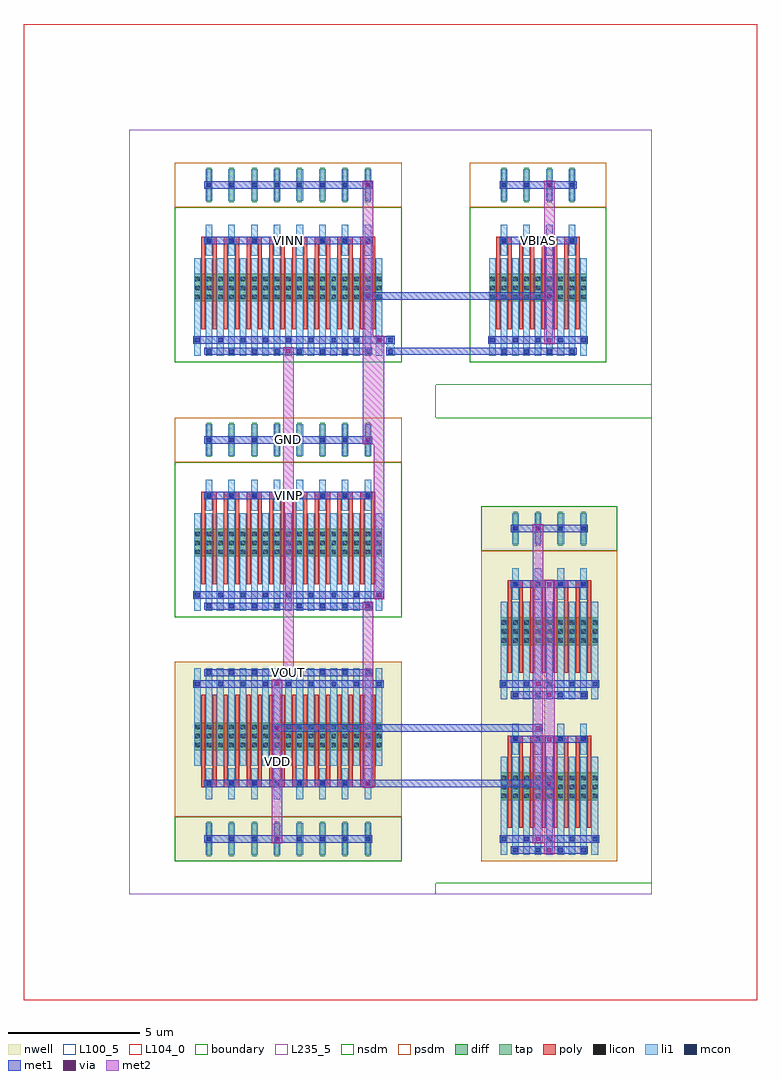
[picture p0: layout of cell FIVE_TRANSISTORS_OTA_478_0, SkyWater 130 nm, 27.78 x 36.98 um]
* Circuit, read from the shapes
.subckt FIVE_TRANSISTORS_OTA_478_0 GND VBIAS VDD VINN VINP VOUT
XM1 n1 VINP n2 GND sky130_fd_pr__nfet_01v8 w=1.05 l=0.15 m=16
XM2 VOUT VINN n2 GND sky130_fd_pr__nfet_01v8 w=1.05 l=0.15 m=16
XM3 n2 VBIAS GND GND sky130_fd_pr__nfet_01v8 w=1.05 l=0.15 m=8
XM4 VOUT n1 VDD VDD sky130_fd_pr__pfet_01v8 w=1.05 l=0.15 m=16
XM5 n1 n1 VDD VDD sky130_fd_pr__pfet_01v8 w=1.05 l=0.15 m=16
.ends

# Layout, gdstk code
from math import pi, radians
import gdstk
lib = gdstk.Library(unit=1e-6, precision=1e-09)
def R(c, l, rs):  # rectangles x0, y0, x1, y1
    for r in rs: c.add(gdstk.rectangle(r[:2], r[2:], *l))
def A(c, l, x, y, w, h, nx, ny, dx, dy):  # array of equal rectangles
    R(c, l, [(x+i*dx, y+j*dy, x+i*dx+w, y+j*dy+h) for i in range(nx) for j in range(ny)])
def P(c, l, *ps):  # polygons
    for p in ps: c.add(gdstk.Polygon(p, *l))
nwell = (64, 20)
diff = (65, 20)
tap = (65, 44)
poly = (66, 20)
licon = (66, 44)
li1 = (67, 20)
mcon = (67, 44)
met1 = (68, 20)
via = (68, 44)
met2 = (69, 20)
nsdm = (93, 44)
psdm = (94, 20)
L100_5 = (100, 5)
L104_0 = (104, 0)
boundary = (235, 4)
L235_5 = (235, 5)

dcl_pmos_s_58408510_x4_y = lib.new_cell('DCL_PMOS_S_58408510_X4_Y2_1746735249')
R(dcl_pmos_s_58408510_x4_y, nwell, [(1.29,0.84,6.45,14.28)])
R(dcl_pmos_s_58408510_x4_y, diff, [(2.025,3.15,5.715,4.2), (2.025,9.03,5.715,10.08)])
A(dcl_pmos_s_58408510_x4_y, tap, 2.495, 12.795, 0.17, 1.29, 4, 1, 0.86, 0)
A(dcl_pmos_s_58408510_x4_y, poly, 2.29, 2.1, 0.15, 3.36, 8, 2, 0.43, 5.88)
A(dcl_pmos_s_58408510_x4_y, poly, 2.29, 5.325, 0.58, 0.27, 4, 2, 0.86, 5.88)
A(dcl_pmos_s_58408510_x4_y, licon, 2.065, 3.23, 0.17, 0.17, 3, 3, 0.43, 0.34)
A(dcl_pmos_s_58408510_x4_y, licon, 2.925, 3.23, 0.17, 0.17, 3, 3, 0.43, 0.34)
A(dcl_pmos_s_58408510_x4_y, licon, 3.785, 3.23, 0.17, 0.17, 3, 3, 0.43, 0.34)
A(dcl_pmos_s_58408510_x4_y, licon, 4.645, 3.23, 0.17, 0.17, 3, 3, 0.43, 0.34)
A(dcl_pmos_s_58408510_x4_y, licon, 2.495, 5.375, 0.17, 0.17, 4, 2, 0.86, 5.88)
A(dcl_pmos_s_58408510_x4_y, licon, 2.065, 9.11, 0.17, 0.17, 3, 3, 0.43, 0.34)
A(dcl_pmos_s_58408510_x4_y, licon, 2.925, 9.11, 0.17, 0.17, 3, 3, 0.43, 0.34)
A(dcl_pmos_s_58408510_x4_y, licon, 3.785, 9.11, 0.17, 0.17, 3, 3, 0.43, 0.34)
A(dcl_pmos_s_58408510_x4_y, licon, 4.645, 9.11, 0.17, 0.17, 3, 3, 0.43, 0.34)
R(dcl_pmos_s_58408510_x4_y, licon, [(2.495,13.355,2.665,13.525), (2.495,13.355,2.665,13.525), (3.355,13.355,3.525,13.525), (3.355,13.355,3.525,13.525), (4.215,13.355,4.385,13.525), (4.215,13.355,4.385,13.525), (5.075,13.355,5.245,13.525), (5.075,13.355,5.245,13.525)])
A(dcl_pmos_s_58408510_x4_y, li1, 2.025, 1.09, 0.25, 3.7, 9, 2, 0.43, 5.88)
A(dcl_pmos_s_58408510_x4_y, li1, 2.455, 4.87, 0.25, 1.18, 4, 2, 0.86, 5.88)
A(dcl_pmos_s_58408510_x4_y, li1, 2.455, 12.85, 0.25, 1.18, 4, 1, 0.86, 0)
A(dcl_pmos_s_58408510_x4_y, mcon, 2.495, 1.175, 0.17, 0.17, 4, 2, 0.86, 4.2)
A(dcl_pmos_s_58408510_x4_y, mcon, 2.065, 1.595, 0.17, 0.17, 5, 2, 0.86, 5.88)
A(dcl_pmos_s_58408510_x4_y, mcon, 2.495, 7.055, 0.17, 0.17, 4, 2, 0.86, 4.2)
A(dcl_pmos_s_58408510_x4_y, mcon, 2.495, 13.355, 0.17, 0.17, 4, 1, 0.86, 0)
R(dcl_pmos_s_58408510_x4_y, met1, [(2.41,1.12,5.33,1.4), (1.98,1.54,5.76,1.82), (2.41,5.32,5.33,5.6), (2.41,7,5.33,7.28), (1.98,7.42,5.76,7.7), (2.41,11.2,5.33,11.48), (2.41,13.3,5.33,13.58)])
A(dcl_pmos_s_58408510_x4_y, via, 4.225, 1.605, 0.15, 0.15, 1, 3, 0, 5.88)
R(dcl_pmos_s_58408510_x4_y, via, [(3.795,1.185,3.945,1.335), (3.795,5.385,3.945,5.535), (3.795,7.065,3.945,7.215), (3.795,11.265,3.945,11.415)])
R(dcl_pmos_s_58408510_x4_y, met2, [(3.67,1.1,4.07,11.5), (4.1,1.52,4.5,13.6)])
R(dcl_pmos_s_58408510_x4_y, nsdm, [(1.29,12.6,6.45,14.28)])
R(dcl_pmos_s_58408510_x4_y, psdm, [(1.29,0.84,6.45,12.6)])
R(dcl_pmos_s_58408510_x4_y, L100_5, [(0,0,8.17,17.64)])
R(dcl_pmos_s_58408510_x4_y, boundary, [(0,0,8.17,17.64)])

nmos_s_69925134_x4_y1_17 = lib.new_cell('NMOS_S_69925134_X4_Y1_1746735252')
R(nmos_s_69925134_x4_y1_17, diff, [(2.025,3.15,5.715,4.2)])
A(nmos_s_69925134_x4_y1_17, tap, 2.495, 6.915, 0.17, 1.29, 4, 1, 0.86, 0)
A(nmos_s_69925134_x4_y1_17, poly, 2.29, 2.1, 0.15, 3.36, 8, 1, 0.43, 0)
A(nmos_s_69925134_x4_y1_17, poly, 2.29, 5.325, 0.58, 0.27, 4, 1, 0.86, 0)
A(nmos_s_69925134_x4_y1_17, licon, 2.065, 3.23, 0.17, 0.17, 3, 3, 0.43, 0.34)
A(nmos_s_69925134_x4_y1_17, licon, 2.925, 3.23, 0.17, 0.17, 3, 3, 0.43, 0.34)
A(nmos_s_69925134_x4_y1_17, licon, 3.785, 3.23, 0.17, 0.17, 3, 3, 0.43, 0.34)
A(nmos_s_69925134_x4_y1_17, licon, 4.645, 3.23, 0.17, 0.17, 3, 3, 0.43, 0.34)
A(nmos_s_69925134_x4_y1_17, licon, 2.495, 5.375, 0.17, 0.17, 4, 2, 0.86, 2.1)
A(nmos_s_69925134_x4_y1_17, li1, 2.025, 1.09, 0.25, 3.7, 9, 1, 0.43, 0)
A(nmos_s_69925134_x4_y1_17, li1, 2.455, 4.87, 0.25, 1.18, 4, 2, 0.86, 2.1)
A(nmos_s_69925134_x4_y1_17, mcon, 2.495, 1.175, 0.17, 0.17, 4, 2, 0.86, 4.2)
A(nmos_s_69925134_x4_y1_17, mcon, 2.065, 1.595, 0.17, 0.17, 5, 1, 0.86, 0)
A(nmos_s_69925134_x4_y1_17, mcon, 2.495, 7.475, 0.17, 0.17, 4, 1, 0.86, 0)
R(nmos_s_69925134_x4_y1_17, met1, [(2.41,1.12,5.33,1.4), (1.98,1.54,5.76,1.82), (2.41,5.32,5.33,5.6), (2.41,7.42,5.33,7.7)])
R(nmos_s_69925134_x4_y1_17, via, [(4.225,1.605,4.375,1.755), (4.225,7.485,4.375,7.635)])
R(nmos_s_69925134_x4_y1_17, met2, [(4.1,1.52,4.5,7.72)])
R(nmos_s_69925134_x4_y1_17, nsdm, [(1.29,0.84,6.45,6.72)])
R(nmos_s_69925134_x4_y1_17, psdm, [(1.29,6.72,6.45,8.4)])
R(nmos_s_69925134_x4_y1_17, L100_5, [(0,0,8.17,9.66)])
R(nmos_s_69925134_x4_y1_17, boundary, [(0,0,8.17,9.66)])

pmos_s_35671219_x8_y1_17 = lib.new_cell('PMOS_S_35671219_X8_Y1_1746735253')
R(pmos_s_35671219_x8_y1_17, nwell, [(1.29,0.84,9.89,8.4)])
R(pmos_s_35671219_x8_y1_17, diff, [(2.025,3.15,9.155,4.2)])
A(pmos_s_35671219_x8_y1_17, tap, 2.495, 6.915, 0.17, 1.29, 8, 1, 0.86, 0)
A(pmos_s_35671219_x8_y1_17, poly, 2.29, 2.1, 0.15, 3.36, 16, 1, 0.43, 0)
A(pmos_s_35671219_x8_y1_17, poly, 2.29, 5.325, 0.58, 0.27, 8, 1, 0.86, 0)
A(pmos_s_35671219_x8_y1_17, licon, 2.065, 3.23, 0.17, 0.17, 3, 3, 0.43, 0.34)
A(pmos_s_35671219_x8_y1_17, licon, 2.925, 3.23, 0.17, 0.17, 3, 3, 0.43, 0.34)
A(pmos_s_35671219_x8_y1_17, licon, 3.785, 3.23, 0.17, 0.17, 3, 3, 0.43, 0.34)
A(pmos_s_35671219_x8_y1_17, licon, 4.645, 3.23, 0.17, 0.17, 3, 3, 0.43, 0.34)
A(pmos_s_35671219_x8_y1_17, licon, 5.505, 3.23, 0.17, 0.17, 3, 3, 0.43, 0.34)
A(pmos_s_35671219_x8_y1_17, licon, 6.365, 3.23, 0.17, 0.17, 3, 3, 0.43, 0.34)
A(pmos_s_35671219_x8_y1_17, licon, 7.225, 3.23, 0.17, 0.17, 3, 3, 0.43, 0.34)
A(pmos_s_35671219_x8_y1_17, licon, 8.085, 3.23, 0.17, 0.17, 3, 3, 0.43, 0.34)
A(pmos_s_35671219_x8_y1_17, licon, 2.495, 5.375, 0.17, 0.17, 8, 2, 0.86, 2.1)
A(pmos_s_35671219_x8_y1_17, li1, 2.025, 1.09, 0.25, 3.7, 17, 1, 0.43, 0)
A(pmos_s_35671219_x8_y1_17, li1, 2.455, 4.87, 0.25, 1.18, 8, 2, 0.86, 2.1)
A(pmos_s_35671219_x8_y1_17, mcon, 2.495, 1.175, 0.17, 0.17, 8, 2, 0.86, 4.2)
A(pmos_s_35671219_x8_y1_17, mcon, 2.065, 1.595, 0.17, 0.17, 9, 1, 0.86, 0)
A(pmos_s_35671219_x8_y1_17, mcon, 2.495, 7.475, 0.17, 0.17, 8, 1, 0.86, 0)
R(pmos_s_35671219_x8_y1_17, met1, [(2.41,1.12,8.77,1.4), (1.98,1.54,9.2,1.82), (2.41,5.32,8.77,5.6), (2.41,7.42,8.77,7.7)])
R(pmos_s_35671219_x8_y1_17, via, [(5.945,1.605,6.095,1.755), (5.945,7.485,6.095,7.635)])
R(pmos_s_35671219_x8_y1_17, met2, [(5.82,1.52,6.22,7.72)])
R(pmos_s_35671219_x8_y1_17, nsdm, [(1.29,6.72,9.89,8.4)])
R(pmos_s_35671219_x8_y1_17, psdm, [(1.29,0.84,9.89,6.72)])
R(pmos_s_35671219_x8_y1_17, L100_5, [(0,0,11.61,9.66)])
R(pmos_s_35671219_x8_y1_17, boundary, [(0,0,11.61,9.66)])

nmos_4t_75119689_x8_y1_1 = lib.new_cell('NMOS_4T_75119689_X8_Y1_1746735251')
R(nmos_4t_75119689_x8_y1_1, diff, [(2.025,3.15,9.155,4.2)])
A(nmos_4t_75119689_x8_y1_1, tap, 2.495, 6.915, 0.17, 1.29, 8, 1, 0.86, 0)
A(nmos_4t_75119689_x8_y1_1, poly, 2.29, 2.1, 0.15, 3.36, 16, 1, 0.43, 0)
A(nmos_4t_75119689_x8_y1_1, poly, 2.29, 5.325, 0.58, 0.27, 8, 1, 0.86, 0)
A(nmos_4t_75119689_x8_y1_1, licon, 2.065, 3.23, 0.17, 0.17, 3, 3, 0.43, 0.34)
A(nmos_4t_75119689_x8_y1_1, licon, 2.925, 3.23, 0.17, 0.17, 3, 3, 0.43, 0.34)
A(nmos_4t_75119689_x8_y1_1, licon, 3.785, 3.23, 0.17, 0.17, 3, 3, 0.43, 0.34)
A(nmos_4t_75119689_x8_y1_1, licon, 4.645, 3.23, 0.17, 0.17, 3, 3, 0.43, 0.34)
A(nmos_4t_75119689_x8_y1_1, licon, 5.505, 3.23, 0.17, 0.17, 3, 3, 0.43, 0.34)
A(nmos_4t_75119689_x8_y1_1, licon, 6.365, 3.23, 0.17, 0.17, 3, 3, 0.43, 0.34)
A(nmos_4t_75119689_x8_y1_1, licon, 7.225, 3.23, 0.17, 0.17, 3, 3, 0.43, 0.34)
A(nmos_4t_75119689_x8_y1_1, licon, 8.085, 3.23, 0.17, 0.17, 3, 3, 0.43, 0.34)
A(nmos_4t_75119689_x8_y1_1, licon, 2.495, 5.375, 0.17, 0.17, 8, 2, 0.86, 2.1)
A(nmos_4t_75119689_x8_y1_1, li1, 2.025, 1.09, 0.25, 3.7, 17, 1, 0.43, 0)
A(nmos_4t_75119689_x8_y1_1, li1, 2.455, 4.87, 0.25, 1.18, 8, 2, 0.86, 2.1)
A(nmos_4t_75119689_x8_y1_1, mcon, 2.495, 1.175, 0.17, 0.17, 8, 2, 0.86, 4.2)
A(nmos_4t_75119689_x8_y1_1, mcon, 2.065, 1.595, 0.17, 0.17, 9, 1, 0.86, 0)
A(nmos_4t_75119689_x8_y1_1, mcon, 2.495, 7.475, 0.17, 0.17, 8, 1, 0.86, 0)
R(nmos_4t_75119689_x8_y1_1, met1, [(2.41,1.12,8.77,1.4), (1.98,1.54,9.2,1.82), (2.41,5.32,8.77,5.6), (2.41,7.42,8.77,7.7)])
R(nmos_4t_75119689_x8_y1_1, nsdm, [(1.29,0.84,9.89,6.72)])
R(nmos_4t_75119689_x8_y1_1, psdm, [(1.29,6.72,9.89,8.4)])
R(nmos_4t_75119689_x8_y1_1, L100_5, [(0,0,11.61,9.66)])
R(nmos_4t_75119689_x8_y1_1, boundary, [(0,0,11.61,9.66)])

nmos_4t_28601550_x8_y1_1 = lib.new_cell('NMOS_4T_28601550_X8_Y1_1746735250')
R(nmos_4t_28601550_x8_y1_1, diff, [(2.025,3.15,9.155,4.2)])
A(nmos_4t_28601550_x8_y1_1, tap, 2.495, 6.915, 0.17, 1.29, 8, 1, 0.86, 0)
A(nmos_4t_28601550_x8_y1_1, poly, 2.29, 2.1, 0.15, 3.36, 16, 1, 0.43, 0)
A(nmos_4t_28601550_x8_y1_1, poly, 2.29, 5.325, 0.58, 0.27, 8, 1, 0.86, 0)
A(nmos_4t_28601550_x8_y1_1, licon, 2.065, 3.23, 0.17, 0.17, 3, 3, 0.43, 0.34)
A(nmos_4t_28601550_x8_y1_1, licon, 2.925, 3.23, 0.17, 0.17, 3, 3, 0.43, 0.34)
A(nmos_4t_28601550_x8_y1_1, licon, 3.785, 3.23, 0.17, 0.17, 3, 3, 0.43, 0.34)
A(nmos_4t_28601550_x8_y1_1, licon, 4.645, 3.23, 0.17, 0.17, 3, 3, 0.43, 0.34)
A(nmos_4t_28601550_x8_y1_1, licon, 5.505, 3.23, 0.17, 0.17, 3, 3, 0.43, 0.34)
A(nmos_4t_28601550_x8_y1_1, licon, 6.365, 3.23, 0.17, 0.17, 3, 3, 0.43, 0.34)
A(nmos_4t_28601550_x8_y1_1, licon, 7.225, 3.23, 0.17, 0.17, 3, 3, 0.43, 0.34)
A(nmos_4t_28601550_x8_y1_1, licon, 8.085, 3.23, 0.17, 0.17, 3, 3, 0.43, 0.34)
A(nmos_4t_28601550_x8_y1_1, licon, 2.495, 5.375, 0.17, 0.17, 8, 2, 0.86, 2.1)
A(nmos_4t_28601550_x8_y1_1, li1, 2.025, 1.09, 0.25, 3.7, 17, 1, 0.43, 0)
A(nmos_4t_28601550_x8_y1_1, li1, 2.455, 4.87, 0.25, 1.18, 8, 2, 0.86, 2.1)
A(nmos_4t_28601550_x8_y1_1, mcon, 2.495, 1.175, 0.17, 0.17, 8, 2, 0.86, 4.2)
A(nmos_4t_28601550_x8_y1_1, mcon, 2.065, 1.595, 0.17, 0.17, 9, 1, 0.86, 0)
A(nmos_4t_28601550_x8_y1_1, mcon, 2.495, 7.475, 0.17, 0.17, 8, 1, 0.86, 0)
R(nmos_4t_28601550_x8_y1_1, met1, [(2.41,1.12,8.77,1.4), (1.98,1.54,9.2,1.82), (2.41,5.32,8.77,5.6), (2.41,7.42,8.77,7.7)])
R(nmos_4t_28601550_x8_y1_1, nsdm, [(1.29,0.84,9.89,6.72)])
R(nmos_4t_28601550_x8_y1_1, psdm, [(1.29,6.72,9.89,8.4)])
R(nmos_4t_28601550_x8_y1_1, L100_5, [(0,0,11.61,9.66)])
R(nmos_4t_28601550_x8_y1_1, boundary, [(0,0,11.61,9.66)])

five_transistors_ota_478 = lib.new_cell('FIVE_TRANSISTORS_OTA_478_0')
R(five_transistors_ota_478, li1, [(9.72,20.41,10.06,20.75), (9.72,20.41,10.06,20.75), (9.765,20.58,10.015,21), (9.72,20.83,10.06,21.17), (9.72,20.83,10.06,21.17)])
R(five_transistors_ota_478, mcon, [(9.805,20.495,9.975,20.665), (9.805,20.495,9.975,20.665), (9.805,20.915,9.975,21.085), (9.805,20.915,9.975,21.085)])
R(five_transistors_ota_478, met1, [(8.87,4.06,9.19,4.34), (8.87,4.06,9.19,4.34), (8.87,4.06,9.19,4.34), (8.87,4.06,9.19,4.34), (9.03,4.06,15.91,4.34), (15.75,4.06,16.07,4.34), (15.75,4.06,16.07,4.34), (5.43,6.16,5.75,6.44), (5.43,6.16,5.75,6.44), (5.59,6.16,15.48,6.44), (15.32,6.16,15.64,6.44), (15.32,6.16,15.64,6.44), (5.86,8.26,6.18,8.54), (5.86,8.26,6.18,8.54), (8.87,10.78,9.19,11.06), (8.87,10.78,9.19,11.06), (8.87,10.78,9.19,11.06), (8.87,10.78,9.19,11.06), (9.3,11.2,9.62,11.48), (9.3,11.2,9.62,11.48), (9.3,11.2,9.62,11.48), (9.3,11.2,9.62,11.48), (8.87,17.08,9.19,17.36), (8.87,17.08,9.19,17.36), (8.87,17.08,9.19,17.36), (8.87,17.08,9.19,17.36), (5.86,20.44,6.18,20.72), (5.86,20.44,6.18,20.72), (9.72,20.44,10.06,20.72), (9.72,20.44,10.06,20.72), (9.89,20.44,14.19,20.72), (9.3,20.86,9.62,21.14), (9.3,20.86,9.62,21.14), (9.3,20.86,9.62,21.14), (9.3,20.86,9.62,21.14), (9.46,20.86,9.89,21.14), (9.72,20.86,10.06,21.14), (9.72,20.86,10.06,21.14), (8.87,22.54,9.19,22.82), (8.87,22.54,9.19,22.82), (9.03,22.54,15.91,22.82), (15.75,22.54,16.07,22.82), (15.75,22.54,16.07,22.82), (8.87,26.74,9.19,27.02), (8.87,26.74,9.19,27.02), (8.87,26.74,9.19,27.02), (8.87,26.74,9.19,27.02)])
P(five_transistors_ota_478, met1, [(0,0),(0,0),(0,0),(0,0)],
  [(0,0),(0,0),(0,0),(0,0)],
  [(0,0),(0,0),(0,0),(0,0)],
  [(0,0),(0,0),(0,0),(0,0)],
  [(0,0),(0,0),(0,0),(0,0)],
  [(0,0),(0,0),(0,0),(0,0)],
  [(0,0),(0,0),(0,0),(0,0)],
  [(0,0),(0,0),(0,0),(0,0)],
  [(0,0),(0,0),(0,0),(0,0)],
  [(0,0),(0,0),(0,0),(0,0)],
  [(0,0),(0,0),(0,0),(0,0)],
  [(0,0),(0,0),(0,0),(0,0)],
  [(0,0),(0,0),(0,0),(0,0)],
  [(0,0),(0,0),(0,0),(0,0)],
  [(0,0),(0,0),(0,0),(0,0)],
  [(0,0),(0,0),(0,0),(0,0)],
  [(0,0),(0,0),(0,0),(0,0)])
R(five_transistors_ota_478, via, [(8.955,4.125,9.105,4.275), (8.955,4.125,9.105,4.275), (8.955,4.125,9.105,4.275), (8.955,4.125,9.105,4.275), (15.835,4.125,15.985,4.275), (15.835,4.125,15.985,4.275), (5.515,6.225,5.665,6.375), (5.515,6.225,5.665,6.375), (15.405,6.225,15.555,6.375), (15.405,6.225,15.555,6.375), (5.945,8.325,6.095,8.475), (5.945,8.325,6.095,8.475), (8.955,10.845,9.105,10.995), (8.955,10.845,9.105,10.995), (8.955,10.845,9.105,10.995), (8.955,10.845,9.105,10.995), (9.385,11.265,9.535,11.415), (9.385,11.265,9.535,11.415), (9.385,11.265,9.535,11.415), (9.385,11.265,9.535,11.415), (8.955,17.145,9.105,17.295), (8.955,17.145,9.105,17.295), (8.955,17.145,9.105,17.295), (8.955,17.145,9.105,17.295), (5.945,20.505,6.095,20.655), (5.945,20.505,6.095,20.655), (9.385,20.925,9.535,21.075), (9.385,20.925,9.535,21.075), (9.385,20.925,9.535,21.075), (9.385,20.925,9.535,21.075), (8.955,22.605,9.105,22.755), (8.955,22.605,9.105,22.755), (15.835,22.605,15.985,22.755), (15.835,22.605,15.985,22.755), (8.955,26.805,9.105,26.955), (8.955,26.805,9.105,26.955), (8.955,26.805,9.105,26.955), (8.955,26.805,9.105,26.955)])
R(five_transistors_ota_478, met2, [(8.83,4.04,9.23,4.36), (8.83,4.04,9.23,4.36), (8.83,4.04,9.23,4.36), (8.83,4.04,9.23,4.36), (15.71,4.04,16.11,4.36), (15.71,4.04,16.11,4.36), (8.83,4.2,9.23,10.92), (5.39,6.14,5.79,6.46), (5.39,6.14,5.79,6.46), (15.28,6.14,15.68,6.46), (15.28,6.14,15.68,6.46), (5.82,8.24,6.22,8.56), (5.82,8.24,6.22,8.56), (5.82,8.4,6.22,20.58), (8.83,10.76,9.23,11.08), (8.83,10.76,9.23,11.08), (8.83,10.76,9.23,11.08), (8.83,10.76,9.23,11.08), (9.26,11.18,9.66,11.5), (9.26,11.18,9.66,11.5), (9.26,11.18,9.66,11.5), (9.26,11.18,9.66,11.5), (9.26,11.34,9.66,21), (8.83,17.06,9.23,17.38), (8.83,17.06,9.23,17.38), (8.83,17.06,9.23,17.38), (8.83,17.06,9.23,17.38), (8.83,17.22,9.23,26.88), (5.82,20.42,6.22,20.74), (5.82,20.42,6.22,20.74), (9.26,20.84,9.66,21.16), (9.26,20.84,9.66,21.16), (9.26,20.84,9.66,21.16), (9.26,20.84,9.66,21.16), (8.83,22.52,9.23,22.84), (8.83,22.52,9.23,22.84), (15.71,22.52,16.11,22.84), (15.71,22.52,16.11,22.84), (8.83,26.72,9.23,27.04), (8.83,26.72,9.23,27.04), (8.83,26.72,9.23,27.04), (8.83,26.72,9.23,27.04)])
P(five_transistors_ota_478, met2, [(0,0),(0,0),(0,0),(0,0)],
  [(0,0),(0,0),(0,0),(0,0)],
  [(0,0),(0,0),(0,0),(0,0)],
  [(0,0),(0,0),(0,0),(0,0)],
  [(0,0),(0,0),(0,0),(0,0)])
R(five_transistors_ota_478, L104_0, [(-4,-4,23.78,32.98)])
R(five_transistors_ota_478, L235_5, [(0,0,19.78,28.98)])
five_transistors_ota_478.add(gdstk.Reference(dcl_pmos_s_58408510_x4_y, (19.78,0.42), rotation=pi, x_reflection=True))
five_transistors_ota_478.add(gdstk.Reference(nmos_s_69925134_x4_y1_17, (11.61,19.32)))
five_transistors_ota_478.add(gdstk.Reference(pmos_s_35671219_x8_y1_17, (11.61,9.66), rotation=pi))
five_transistors_ota_478.add(gdstk.Reference(nmos_4t_75119689_x8_y1_1, (11.61,19.32), rotation=pi, x_reflection=True))
five_transistors_ota_478.add(gdstk.Reference(nmos_4t_28601550_x8_y1_1, (11.61,9.66), rotation=pi, x_reflection=True))
five_transistors_ota_478.add(gdstk.Label('VDD', (5.59,5.04), layer=69, texttype=5))
five_transistors_ota_478.add(gdstk.Label('VBIAS', (15.48,24.78), layer=68, texttype=5))
five_transistors_ota_478.add(gdstk.Label('GND', (6.02,17.22), layer=68, texttype=5))
five_transistors_ota_478.add(gdstk.Label('VOUT', (6.02,8.4), layer=68, texttype=5))
five_transistors_ota_478.add(gdstk.Label('VINN', (6.02,24.78), layer=68, texttype=5))
five_transistors_ota_478.add(gdstk.Label('VINP', (6.02,15.12), layer=68, texttype=5))

lib.write_gds('FIVE_TRANSISTORS_OTA_478_0.gds')
